One B-rep face of a CAD part: STEP entity #445.
In plain terms, the planar face has unit normal (1, 0, 0).
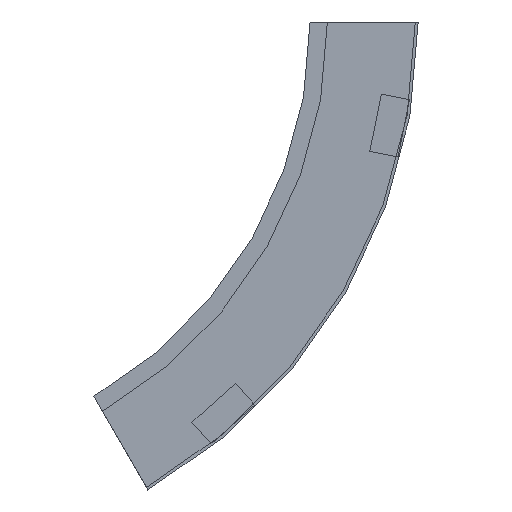
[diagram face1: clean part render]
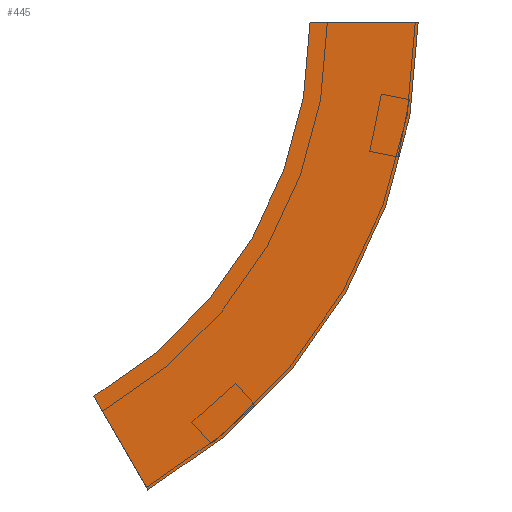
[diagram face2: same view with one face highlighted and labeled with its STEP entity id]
Its self-contained STEP definition (entity closure, numbers rounded to 3 decimals):
#21 = DIRECTION ( 'NONE',  ( 0., 1., 0. ) ) ;
#33 = CIRCLE ( 'NONE', #453, 375. ) ;
#38 = ORIENTED_EDGE ( 'NONE', *, *, #269, .F. ) ;
#39 = CIRCLE ( 'NONE', #431, 300. ) ;
#55 = ORIENTED_EDGE ( 'NONE', *, *, #77, .F. ) ;
#63 = CARTESIAN_POINT ( 'NONE',  ( 0., 112.5, -324.76 ) ) ;
#77 = EDGE_CURVE ( 'NONE', #368, #243, #39, .T. ) ;
#95 = DIRECTION ( 'NONE',  ( 0., 0., 1. ) ) ;
#117 = EDGE_CURVE ( 'NONE', #240, #243, #396, .T. ) ;
#138 = DIRECTION ( 'NONE',  ( 0., -1., 0. ) ) ;
#157 = CARTESIAN_POINT ( 'NONE',  ( 0., 0., 0. ) ) ;
#179 = DIRECTION ( 'NONE',  ( 0., 0.5, 0.866 ) ) ;
#200 = ORIENTED_EDGE ( 'NONE', *, *, #117, .T. ) ;
#218 = FACE_OUTER_BOUND ( 'NONE', #393, .T. ) ;
#235 = LINE ( 'NONE', #413, #253 ) ;
#238 = CARTESIAN_POINT ( 'NONE',  ( 0., 150., -259.808 ) ) ;
#240 = VERTEX_POINT ( 'NONE', #63 ) ;
#243 = VERTEX_POINT ( 'NONE', #238 ) ;
#253 = VECTOR ( 'NONE', #21, 1000. ) ;
#260 = CARTESIAN_POINT ( 'NONE',  ( 0., -75., 0. ) ) ;
#261 = ORIENTED_EDGE ( 'NONE', *, *, #511, .T. ) ;
#262 = VECTOR ( 'NONE', #179, 1000. ) ;
#269 = EDGE_CURVE ( 'NONE', #410, #368, #235, .T. ) ;
#283 = AXIS2_PLACEMENT_3D ( 'NONE', #260, #493, #95 ) ;
#310 = DIRECTION ( 'NONE',  ( 0., -1., 0. ) ) ;
#337 = CARTESIAN_POINT ( 'NONE',  ( 0., -75., 0. ) ) ;
#355 = DIRECTION ( 'NONE',  ( 1., 0., 0. ) ) ;
#368 = VERTEX_POINT ( 'NONE', #157 ) ;
#392 = PLANE ( 'NONE',  #283 ) ;
#393 = EDGE_LOOP ( 'NONE', ( #55, #38, #261, #200 ) ) ;
#395 = CARTESIAN_POINT ( 'NONE',  ( 0., 300., 0. ) ) ;
#396 = LINE ( 'NONE', #450, #262 ) ;
#410 = VERTEX_POINT ( 'NONE', #337 ) ;
#413 = CARTESIAN_POINT ( 'NONE',  ( 0., -75., 0. ) ) ;
#431 = AXIS2_PLACEMENT_3D ( 'NONE', #395, #527, #310 ) ;
#445 = ADVANCED_FACE ( 'NONE', ( #218 ), #392, .F. ) ;
#450 = CARTESIAN_POINT ( 'NONE',  ( 0., 112.5, -324.76 ) ) ;
#451 = CARTESIAN_POINT ( 'NONE',  ( 0., 300., 0. ) ) ;
#453 = AXIS2_PLACEMENT_3D ( 'NONE', #451, #355, #138 ) ;
#493 = DIRECTION ( 'NONE',  ( -1., 0., 0. ) ) ;
#511 = EDGE_CURVE ( 'NONE', #410, #240, #33, .T. ) ;
#527 = DIRECTION ( 'NONE',  ( 1., 0., 0. ) ) ;
